One B-rep face of a CAD part: STEP entity #1405.
In plain terms, the planar face has unit normal (-1, 0, 0).
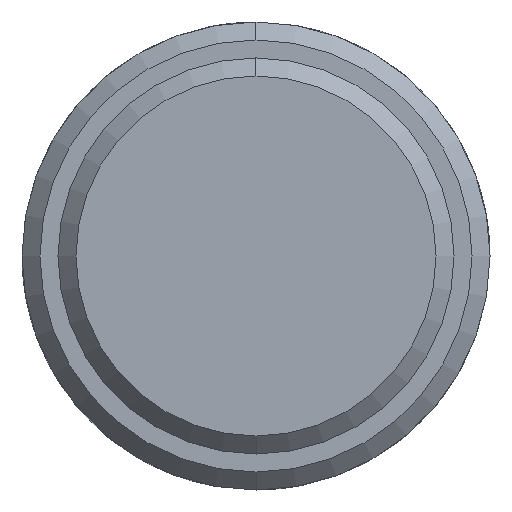
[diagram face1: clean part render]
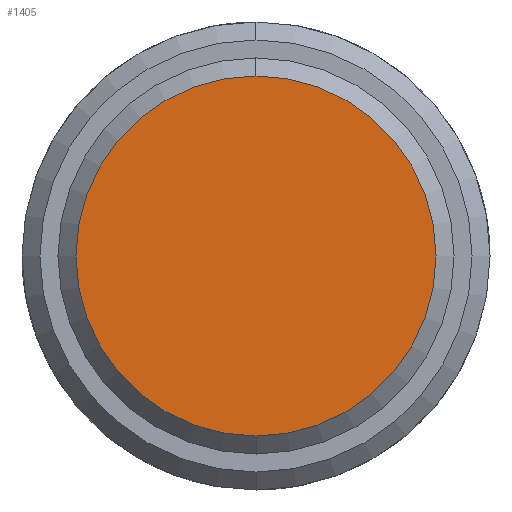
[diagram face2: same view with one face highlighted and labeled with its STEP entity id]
Its self-contained STEP definition (entity closure, numbers rounded to 3 decimals):
#1337=CARTESIAN_POINT('Vertex',(-15.,0.,-10.)) ;
#1340=CARTESIAN_POINT('Axis2P3D Location',(-15.,0.,0.)) ;
#1344=CARTESIAN_POINT('Vertex',(-15.,10.,0.)) ;
#1347=CARTESIAN_POINT('Axis2P3D Location',(-15.,0.,0.)) ;
#1351=CARTESIAN_POINT('Vertex',(-15.,0.,10.)) ;
#1373=CARTESIAN_POINT('Axis2P3D Location',(-15.,0.,0.)) ;
#1377=CARTESIAN_POINT('Vertex',(-15.,-10.,0.)) ;
#1380=CARTESIAN_POINT('Axis2P3D Location',(-15.,0.,0.)) ;
#1394=CARTESIAN_POINT('Axis2P3D Location',(-15.,0.,0.)) ;
#1341=DIRECTION('Axis2P3D Direction',(1.,0.,-0.)) ;
#1348=DIRECTION('Axis2P3D Direction',(1.,0.,-0.)) ;
#1374=DIRECTION('Axis2P3D Direction',(1.,0.,-0.)) ;
#1381=DIRECTION('Axis2P3D Direction',(1.,0.,-0.)) ;
#1395=DIRECTION('Axis2P3D Direction',(1.,0.,-0.)) ;
#1396=DIRECTION('Axis2P3D XDirection',(-0.,0.,-1.)) ;
#1342=AXIS2_PLACEMENT_3D('Circle Axis2P3D',#1340,#1341,$) ;
#1349=AXIS2_PLACEMENT_3D('Circle Axis2P3D',#1347,#1348,$) ;
#1375=AXIS2_PLACEMENT_3D('Circle Axis2P3D',#1373,#1374,$) ;
#1382=AXIS2_PLACEMENT_3D('Circle Axis2P3D',#1380,#1381,$) ;
#1397=AXIS2_PLACEMENT_3D('Plane Axis2P3D',#1394,#1395,#1396) ;
#1400=ORIENTED_EDGE('',*,*,#1346,.F.) ;
#1401=ORIENTED_EDGE('',*,*,#1384,.F.) ;
#1402=ORIENTED_EDGE('',*,*,#1379,.F.) ;
#1403=ORIENTED_EDGE('',*,*,#1353,.F.) ;
#1405=ADVANCED_FACE('357-16X56X90',(#1404),#1398,.F.) ;
#1343=CIRCLE('generated circle',#1342,10.) ;
#1350=CIRCLE('generated circle',#1349,10.) ;
#1376=CIRCLE('generated circle',#1375,10.) ;
#1383=CIRCLE('generated circle',#1382,10.) ;
#1346=EDGE_CURVE('',#1338,#1345,#1343,.T.) ;
#1353=EDGE_CURVE('',#1345,#1352,#1350,.T.) ;
#1379=EDGE_CURVE('',#1352,#1378,#1376,.T.) ;
#1384=EDGE_CURVE('',#1378,#1338,#1383,.T.) ;
#1399=EDGE_LOOP('',(#1400,#1401,#1402,#1403)) ;
#1404=FACE_OUTER_BOUND('',#1399,.T.) ;
#1398=PLANE('Plane',#1397) ;
#1338=VERTEX_POINT('',#1337) ;
#1345=VERTEX_POINT('',#1344) ;
#1352=VERTEX_POINT('',#1351) ;
#1378=VERTEX_POINT('',#1377) ;
